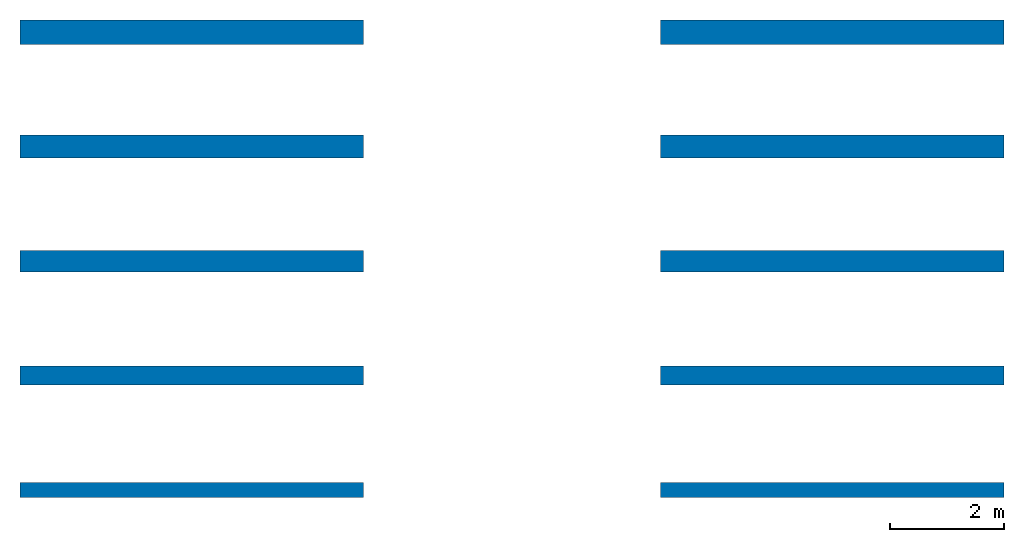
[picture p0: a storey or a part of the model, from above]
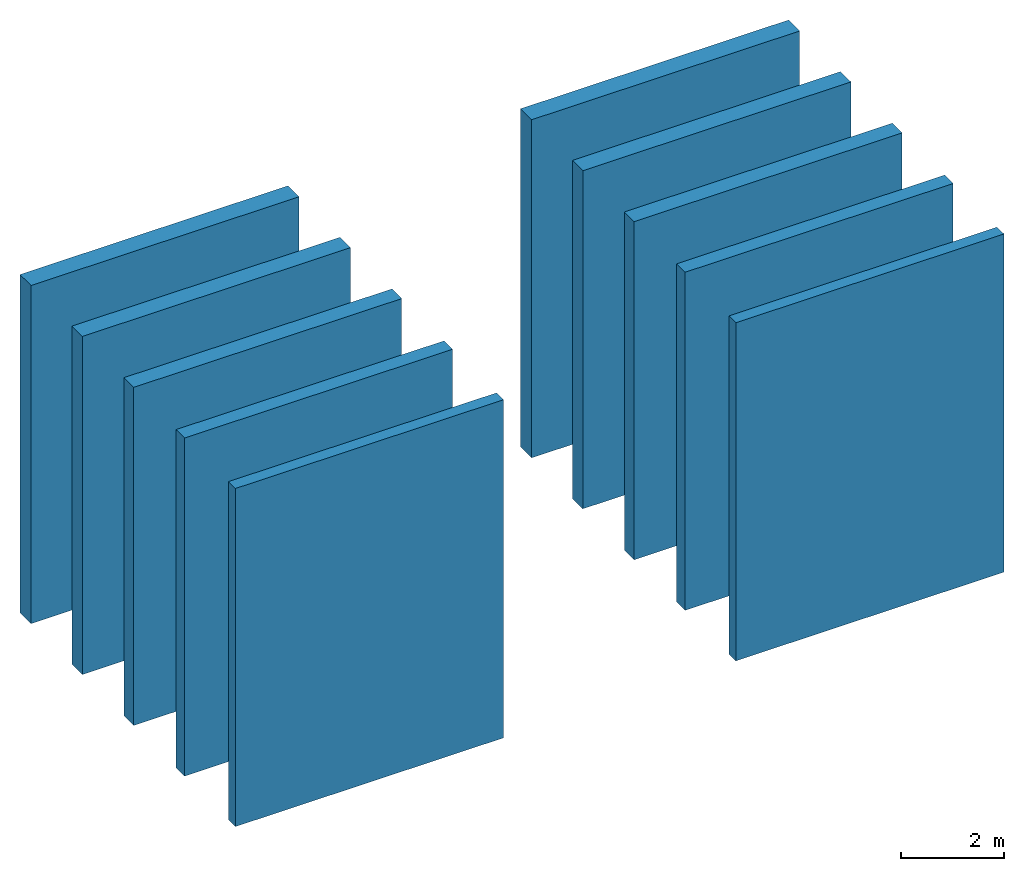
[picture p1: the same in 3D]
Properties of the parts of a building model (IFC2X3)

# File
Description: ViewDefinition [CoordinationView]
File name: Numero
Time: 2019-05-03T09:56:53
Written by: The EXPRESS Data Manager Version 5.02.0100.07 : 28 Aug 2013
Made in: 20150220_1215(x64) - Exporter 16.0.428.0 - Default UI
Comment: STEP Physical File produced by: The EXPRESS Data Manager Version 5.02.0100.07 : 28 Aug 2013 * Module: EDMstepFileFactory/EDMstandAlone * Creation date: Fri May 03 09:56:53 2019 * Host: HP-RS * Database: C:\Users\EKORU_~1\AppData\Local\Temp\{95BD32D2-B268-45CA-9EE8-7F0DB97342BE}\ifc * Database version: 5507 * Database creation date: Fri May 03 09:56:53 2019 * Schema: IFC2X3 * Model: DataRepository.ifc * Model creation date: Fri May 03 09:56:53 2019 * Header model: DataRepository.ifc_HeaderModel * Header model creation date: Fri May 03 09:56:53 2019 * EDMuser: sdai-user * EDMgroup: sdai-group * License ID and type: 5605 : Permanent license. Expiry date: * EDMstepFileFactory options: 020000

# IfcProject, Numero
LongName: Nome; Phase: Stato

# IfcSite, Default
RefLatitude: 41, 47, 59, 999999; RefLongitude: 12, 35, 59, 999999; RefElevation: 0 mm
Altro - Categoria: Informazioni sul progetto; Data di consegna del progetto: Data; Indirizzo del progetto: Immettere l'indirizzo; Nome del cliente: Proprietario; Nome del progetto: Nome; Numero del progetto: Numero; Stato del progetto: Stato

# IfcBuilding
Pset_BuildingCommon - NumberOfStoreys: 1
Altro - Categoria: Informazioni sul progetto; Data di consegna del progetto: Data; Indirizzo del progetto: Immettere l'indirizzo; Nome del cliente: Proprietario; Nome del progetto: Nome; Numero del progetto: Numero; Stato del progetto: Stato

# IfcBuildingStorey, Livello 1
LongName: Livello 1; Elevation: 0 mm
Vincoli - Base quota altimetrica: Punto base progetto; Quota altimetrica: 0 mm
Altro - Categoria: Livelli; Famiglia: Livello: Estremità 8 mm; Famiglia e tipo: Livello: Estremità 8 mm; ID tipo: Livello: Estremità 8 mm; Tipo: Livello: Estremità 8 mm; Nome famiglia: Livello
Dati identità - Strutturale: no; Nome: Livello 1; Piano edificio: yes; Nome del tipo: Estremità 8 mm
Dimensioni - Altezza di calcolo: 0 mm
Grafica - Colore: 0; Modello di linea: Centro; Simbolo: Estremità del livello - Cerchio: Estremità del livello - Cerchio; Simbolo a estremità 1 per default: no; Simbolo a estremità 2 per default: yes; Spessore di linea: 1

# IfcWallStandardCase: Muro di base:Sistema GASBETON Sysmic sp. 269 mm muratura portante, Muro di base:Sistema GASBETON Sysmic sp. 269 mm muratura portante:139188
In: Livello 1
Type - PredefinedType: STANDARD; Material: tonachino colorato ai silicati/silossani di finitura 2 mm, GASBETON Multiraso esterni 5 mm, GASBETON Multicem 15 mm, GASBETON Sysmic 240 mm, GASBETON Incollarasa 5 mm, GASBETON Multiraso interni 2 mm
Type - Altro - Categoria: Muri; Nome famiglia: Muro di base
Type - Costruzione - Funzione: Esterno; Ripiegatura agli inserti: Non ripiegare; Ripiegatura alle estremità: Nessuno; Larghezza: 269 mm
Type - Dati identità - Descrizione: Parete rifinita formata dalla seguente stratigrafia (dall'esterno verso l'interno): tonachino colorato ai silicati/silossani, Multiraso esterni, rete da intonaco GASBETON, Multicem, blocchi GASBETON Sysmic, Incollarasa, rete da intonaco GASBETON, Multira; Installation Guide: http://www.gasbeton.it/wp-content/uploads/2017/11/GASBETON-Guida-alla-progettazione.pdf; Modello: Soluzione muratura esterna portante Gasbeton Sysmic; Nome del tipo: Sistema GASBETON Sysmic sp. 269 mm muratura portante; Product data url: www.gasbeton.it; Produttore: EKORU s.r.l.; Resistenza al fuoco: REI 180; EI 240; Euroclasse A1; Techinical data sheet: http://www.gasbeton.it/download/; URL: http://www.ekoru.it/; Youtube channel: https://www.youtube.com/user/bacchispa
Type - Generale - Edition number: 1; Manufacturer country: Italy; Manufacturer name: EKORU s.r.l.; Product family: walls
Type - Grafica - Colore del retino a dettaglio basso: 0
Type - Materiali e finiture - Materiale strutturale: GASBETON Sysmic; Material main: Autoclaved Aerated Concrete (AAC)
Type - Proprietà analitiche - Ruvidità: 2; Assorbimento: 0.7; Coefficiente di scambio termico (U): 0.409046; Massa termica: 512544; Resistenza termica (R): 2.44471
Altro - Famiglia: Muro di base: Sistema GASBETON Sysmic sp. 269 mm muratura portante; Famiglia e tipo: Muro di base: Sistema GASBETON Sysmic sp. 269 mm muratura portante; ID tipo: Muro di base: Sistema GASBETON Sysmic sp. 269 mm muratura portante; Tipo: Muro di base: Sistema GASBETON Sysmic sp. 269 mm muratura portante
Dimensioni - Area: 48 m2; Lunghezza: 6000 mm; Volume: 12.912 m3
Fasi - Fase di creazione: Fase 1
Strutturale - Attiva modello analitico: no; Strutturale: no; Utilizzo strutturale: Non portante
Vincoli - Delimita il locale: yes; Distanza estensione base: 0 mm; Distanza estensione superiore: 0 mm; La base è associata: no; La parte superiore è associata: no; Linea di ubicazione: Linea d'asse del muro; Offset base: 0 mm; Offset superiore: 0 mm; Relativo a massa: no; Vincolo di base: Livello: Livello 1; Altezza non collegata: 8000 mm
Pset_WallCommon - LoadBearing: no; ExtendToStructure: no; IsExternal: yes; Reference: Sistema GASBETON Sysmic sp. 269 mm muratura portante; FireRating: REI 180; EI 240; Euroclasse A1; ThermalTransmittance: 0.409046 kg/K/s3
Pset_ManufacturerTypeInformation - Manufacturer: EKORU s.r.l.

# IfcWallStandardCase: Muro di base:Sistema GASBETON Sysmic sp. 329 mm muratura portante, Muro di base:Sistema GASBETON Sysmic sp. 329 mm muratura portante:139180
In: Livello 1
Type - PredefinedType: STANDARD; Material: tonachino colorato ai silicati/silossani di finitura 2 mm, GASBETON Multiraso esterni 5 mm, GASBETON Multicem 15 mm, GASBETON Sysmic 300 mm, GASBETON Incollarasa 5 mm, GASBETON Multiraso interni 2 mm
Type - Altro - Categoria: Muri; Nome famiglia: Muro di base
Type - Costruzione - Funzione: Esterno; Ripiegatura agli inserti: Non ripiegare; Ripiegatura alle estremità: Nessuno; Larghezza: 329 mm
Type - Dati identità - Descrizione: Parete rifinita formata dalla seguente stratigrafia (dall'esterno verso l'interno): tonachino colorato ai silicati/silossani, Multiraso esterni, rete da intonaco GASBETON, Multicem, blocchi GASBETON Sysmic, Incollarasa, rete da intonaco GASBETON, Multira; Installation Guide: http://www.gasbeton.it/wp-content/uploads/2017/11/GASBETON-Guida-alla-progettazione.pdf; Modello: Soluzione muratura esterna portante Gasbeton Sysmic; Nome del tipo: Sistema GASBETON Sysmic sp. 329 mm muratura portante; Product data url: www.gasbeton.it; Produttore: EKORU s.r.l.; Resistenza al fuoco: REI 240; Euroclasse A1; Techinical data sheet: http://www.gasbeton.it/download/; URL: http://www.ekoru.it/; Youtube channel: https://www.youtube.com/user/bacchispa
Type - Generale - Edition number: 1; Manufacturer country: Italy; Manufacturer name: EKORU s.r.l.; Product family: walls
Type - Grafica - Colore del retino a dettaglio basso: 0
Type - Materiali e finiture - Materiale strutturale: GASBETON Sysmic; Material main: Autoclaved Aerated Concrete (AAC)
Type - Proprietà analitiche - Ruvidità: 2; Assorbimento: 0.7; Coefficiente di scambio termico (U): 0.329608; Massa termica: 633744; Resistenza termica (R): 3.03391
Altro - Famiglia: Muro di base: Sistema GASBETON Sysmic sp. 329 mm muratura portante; Famiglia e tipo: Muro di base: Sistema GASBETON Sysmic sp. 329 mm muratura portante; ID tipo: Muro di base: Sistema GASBETON Sysmic sp. 329 mm muratura portante; Tipo: Muro di base: Sistema GASBETON Sysmic sp. 329 mm muratura portante
Dimensioni - Area: 48 m2; Lunghezza: 6000 mm; Volume: 15.792 m3
Fasi - Fase di creazione: Fase 1
Strutturale - Attiva modello analitico: no; Strutturale: no; Utilizzo strutturale: Non portante
Vincoli - Delimita il locale: yes; Distanza estensione base: 0 mm; Distanza estensione superiore: 0 mm; La base è associata: no; La parte superiore è associata: no; Linea di ubicazione: Linea d'asse del muro; Offset base: 0 mm; Offset superiore: 0 mm; Relativo a massa: no; Vincolo di base: Livello: Livello 1; Altezza non collegata: 8000 mm
Pset_WallCommon - LoadBearing: no; ExtendToStructure: no; IsExternal: yes; Reference: Sistema GASBETON Sysmic sp. 329 mm muratura portante; FireRating: REI 240; Euroclasse A1; ThermalTransmittance: 0.329608 kg/K/s3
Pset_ManufacturerTypeInformation - Manufacturer: EKORU s.r.l.

# IfcWallStandardCase: Muro di base:Sistema GASBETON Sysmic sp. 379 mm muratura portante, Muro di base:Sistema GASBETON Sysmic sp. 379 mm muratura portante:139172
In: Livello 1
Type - PredefinedType: STANDARD; Material: tonachino colorato ai silicati/silossani di finitura 2 mm, GASBETON Multiraso esterni 5 mm, GASBETON Multicem 15 mm, GASBETON Sysmic 350 mm, GASBETON Incollarasa 5 mm, GASBETON Multiraso interni 2 mm
Type - Altro - Categoria: Muri; Nome famiglia: Muro di base
Type - Costruzione - Funzione: Esterno; Ripiegatura agli inserti: Non ripiegare; Ripiegatura alle estremità: Nessuno; Larghezza: 379 mm
Type - Dati identità - Descrizione: Parete rifinita formata dalla seguente stratigrafia (dall'esterno verso l'interno): tonachino colorato ai silicati/silossani, Multiraso esterni, rete da intonaco GASBETON, Multicem, blocchi GASBETON Sysmic, Incollarasa, rete da intonaco GASBETON, Multira; Installation Guide: http://www.gasbeton.it/wp-content/uploads/2017/11/GASBETON-Guida-alla-progettazione.pdf; Modello: Soluzione muratura esterna portante Gasbeton Sysmic; Nome del tipo: Sistema GASBETON Sysmic sp. 379 mm muratura portante; Product data url: www.gasbeton.it; Produttore: EKORU s.r.l.; Resistenza al fuoco: REI 240; Euroclasse A1; Techinical data sheet: http://www.gasbeton.it/download/; URL: http://www.ekoru.it/; Youtube channel: https://www.youtube.com/user/bacchispa
Type - Generale - Edition number: 1; Manufacturer country: Italy; Manufacturer name: EKORU s.r.l.; Product family: walls
Type - Grafica - Colore del retino a dettaglio basso: 0
Type - Materiali e finiture - Materiale strutturale: GASBETON Sysmic; Material main: Autoclaved Aerated Concrete (AAC)
Type - Proprietà analitiche - Ruvidità: 2; Assorbimento: 0.7; Coefficiente di scambio termico (U): 0.283695; Massa termica: 734744; Resistenza termica (R): 3.52491
Altro - Famiglia: Muro di base: Sistema GASBETON Sysmic sp. 379 mm muratura portante; Famiglia e tipo: Muro di base: Sistema GASBETON Sysmic sp. 379 mm muratura portante; ID tipo: Muro di base: Sistema GASBETON Sysmic sp. 379 mm muratura portante; Tipo: Muro di base: Sistema GASBETON Sysmic sp. 379 mm muratura portante
Dimensioni - Area: 48 m2; Lunghezza: 6000 mm; Volume: 18.192 m3
Fasi - Fase di creazione: Fase 1
Strutturale - Attiva modello analitico: no; Strutturale: no; Utilizzo strutturale: Non portante
Vincoli - Delimita il locale: yes; Distanza estensione base: 0 mm; Distanza estensione superiore: 0 mm; La base è associata: no; La parte superiore è associata: no; Linea di ubicazione: Linea d'asse del muro; Offset base: 0 mm; Offset superiore: 0 mm; Relativo a massa: no; Vincolo di base: Livello: Livello 1; Altezza non collegata: 8000 mm
Pset_WallCommon - LoadBearing: no; ExtendToStructure: no; IsExternal: yes; Reference: Sistema GASBETON Sysmic sp. 379 mm muratura portante; FireRating: REI 240; Euroclasse A1; ThermalTransmittance: 0.283695 kg/K/s3
Pset_ManufacturerTypeInformation - Manufacturer: EKORU s.r.l.

# IfcWallStandardCase: Muro di base:Sistema GASBETON Sysmic sp. 404 mm muratura portante, Muro di base:Sistema GASBETON Sysmic sp. 404 mm muratura portante:139164
In: Livello 1
Type - PredefinedType: STANDARD; Material: tonachino colorato ai silicati/silossani di finitura 2 mm, GASBETON Multiraso esterni 5 mm, GASBETON Multicem 15 mm, GASBETON Sysmic 375 mm, GASBETON Incollarasa 5 mm, GASBETON Multiraso interni 2 mm
Type - Altro - Categoria: Muri; Nome famiglia: Muro di base
Type - Costruzione - Funzione: Esterno; Ripiegatura agli inserti: Non ripiegare; Ripiegatura alle estremità: Nessuno; Larghezza: 404 mm
Type - Dati identità - Descrizione: Parete rifinita formata dalla seguente stratigrafia (dall'esterno verso l'interno): tonachino colorato ai silicati/silossani, Multiraso esterni, rete da intonaco GASBETON, Multicem, blocchi GASBETON Sysmic, Incollarasa, rete da intonaco GASBETON, Multira; Installation Guide: http://www.gasbeton.it/wp-content/uploads/2017/11/GASBETON-Guida-alla-progettazione.pdf; Modello: Soluzione muratura esterna portante Gasbeton Sysmic; Nome del tipo: Sistema GASBETON Sysmic sp. 404 mm muratura portante; Product data url: www.gasbeton.it; Produttore: EKORU s.r.l.; Resistenza al fuoco: REI 240; Euroclasse A1; Techinical data sheet: http://www.gasbeton.it/download/; URL: http://www.ekoru.it/; Youtube channel: https://www.youtube.com/user/bacchispa
Type - Generale - Edition number: 1; Manufacturer country: Italy; Manufacturer name: EKORU s.r.l.; Product family: walls
Type - Grafica - Colore del retino a dettaglio basso: 0
Type - Materiali e finiture - Materiale strutturale: GASBETON Sysmic; Material main: Autoclaved Aerated Concrete (AAC)
Type - Proprietà analitiche - Ruvidità: 2; Assorbimento: 0.7; Coefficiente di scambio termico (U): 0.265223; Massa termica: 785244; Resistenza termica (R): 3.77041
Altro - Famiglia: Muro di base: Sistema GASBETON Sysmic sp. 404 mm muratura portante; Famiglia e tipo: Muro di base: Sistema GASBETON Sysmic sp. 404 mm muratura portante; ID tipo: Muro di base: Sistema GASBETON Sysmic sp. 404 mm muratura portante; Tipo: Muro di base: Sistema GASBETON Sysmic sp. 404 mm muratura portante
Dimensioni - Area: 48 m2; Lunghezza: 6000 mm; Volume: 19.392 m3
Fasi - Fase di creazione: Fase 1
Strutturale - Attiva modello analitico: no; Strutturale: no; Utilizzo strutturale: Non portante
Vincoli - Delimita il locale: yes; Distanza estensione base: 0 mm; Distanza estensione superiore: 0 mm; La base è associata: no; La parte superiore è associata: no; Linea di ubicazione: Linea d'asse del muro; Offset base: 0 mm; Offset superiore: 0 mm; Relativo a massa: no; Vincolo di base: Livello: Livello 1; Altezza non collegata: 8000 mm
Pset_WallCommon - LoadBearing: no; ExtendToStructure: no; IsExternal: yes; Reference: Sistema GASBETON Sysmic sp. 404 mm muratura portante; FireRating: REI 240; Euroclasse A1; ThermalTransmittance: 0.265223 kg/K/s3
Pset_ManufacturerTypeInformation - Manufacturer: EKORU s.r.l.

# IfcWallStandardCase: Muro di base:Sistema GASBETON Sysmic sp. 429 mm muratura portante, Muro di base:Sistema GASBETON Sysmic sp. 429 mm muratura portante:139156
In: Livello 1
Type - PredefinedType: STANDARD; Material: tonachino colorato ai silicati/silossani di finitura 2 mm, GASBETON Multiraso esterni 5 mm, GASBETON Multicem 15 mm, GASBETON Sysmic 400 mm, GASBETON Incollarasa 5 mm, GASBETON Multiraso interni 2 mm
Type - Altro - Categoria: Muri; Nome famiglia: Muro di base
Type - Costruzione - Funzione: Esterno; Larghezza: 429 mm; Ripiegatura agli inserti: Non ripiegare; Ripiegatura alle estremità: Nessuno
Type - Dati identità - Descrizione: Parete rifinita formata dalla seguente stratigrafia (dall'esterno verso l'interno): tonachino colorato ai silicati/silossani, Multiraso esterni, rete da intonaco GASBETON, Multicem, blocchi GASBETON Sysmic, Incollarasa, rete da intonaco GASBETON, Multira; Installation Guide: http://www.gasbeton.it/wp-content/uploads/2017/11/GASBETON-Guida-alla-progettazione.pdf; Modello: Soluzione muratura esterna portante Gasbeton Sysmic; Nome del tipo: Sistema GASBETON Sysmic sp. 429 mm muratura portante; Product data url: www.gasbeton.it; Produttore: EKORU s.r.l.; Resistenza al fuoco: REI 240; Euroclasse A1; Techinical data sheet: http://www.gasbeton.it/download/; URL: http://www.ekoru.it/; Youtube channel: https://www.youtube.com/user/bacchispa
Type - Generale - Edition number: 1; Manufacturer country: Italy; Manufacturer name: EKORU s.r.l.; Product family: walls
Type - Grafica - Colore del retino a dettaglio basso: 0
Type - Materiali e finiture - Materiale strutturale: GASBETON Sysmic; Material main: Autoclaved Aerated Concrete (AAC)
Type - Proprietà analitiche - Assorbimento: 0.7; Coefficiente di scambio termico (U): 0.24901; Massa termica: 835744; Resistenza termica (R): 4.01591; Ruvidità: 2
Altro - Famiglia: Muro di base: Sistema GASBETON Sysmic sp. 429 mm muratura portante; Famiglia e tipo: Muro di base: Sistema GASBETON Sysmic sp. 429 mm muratura portante; ID tipo: Muro di base: Sistema GASBETON Sysmic sp. 429 mm muratura portante; Tipo: Muro di base: Sistema GASBETON Sysmic sp. 429 mm muratura portante
Dimensioni - Area: 48 m2; Lunghezza: 6000 mm; Volume: 20.592 m3
Fasi - Fase di creazione: Fase 1
Strutturale - Attiva modello analitico: no; Strutturale: no; Utilizzo strutturale: Non portante
Vincoli - Altezza non collegata: 8000 mm; Delimita il locale: yes; Distanza estensione base: 0 mm; Distanza estensione superiore: 0 mm; La base è associata: no; La parte superiore è associata: no; Linea di ubicazione: Linea d'asse del muro; Offset base: 0 mm; Offset superiore: 0 mm; Relativo a massa: no; Vincolo di base: Livello: Livello 1
Pset_WallCommon - Reference: Sistema GASBETON Sysmic sp. 429 mm muratura portante; LoadBearing: no; ExtendToStructure: no; IsExternal: yes; FireRating: REI 240; Euroclasse A1; ThermalTransmittance: 0.24901 kg/K/s3
Pset_ManufacturerTypeInformation - Manufacturer: EKORU s.r.l.

# IfcWallStandardCase: Muro di base:Sistema GASBETON Sysmic+ IDRO sp. 269 mm muratura portante, Muro di base:Sistema GASBETON Sysmic+ IDRO sp. 269 mm muratura portante:139192
In: Livello 1
Type - PredefinedType: STANDARD; Material: tonachino colorato ai silicati/silossani di finitura 2 mm, GASBETON Multiraso esterni 5 mm, GASBETON Multicem 15 mm, GASBETON Sysmic 240 mm, GASBETON Incollarasa 5 mm, GASBETON Multiraso interni 2 mm
Type - Altro - Categoria: Muri; Nome famiglia: Muro di base
Type - Costruzione - Funzione: Esterno; Ripiegatura agli inserti: Non ripiegare; Ripiegatura alle estremità: Nessuno; Larghezza: 269 mm
Type - Dati identità - Descrizione: Parete rifinita formata dalla seguente stratigrafia (dall'esterno verso l'interno): tonachino colorato ai silicati/silossani, Multiraso esterni, rete da intonaco GASBETON, Multicem, blocchi GASBETON Sysmic, Incollarasa, rete da intonaco GASBETON, Multira; Installation Guide: http://www.gasbeton.it/wp-content/uploads/2017/11/GASBETON-Guida-alla-progettazione.pdf; Modello: Soluzione muratura esterna portante Gasbeton Sysmic con primo corso idrofobizzato; Nome del tipo: Sistema GASBETON Sysmic+ IDRO sp. 269 mm muratura portante; Product data url: www.gasbeton.it; Produttore: EKORU s.r.l.; Resistenza al fuoco: REI 180; EI 240; Euroclasse A1; Techinical data sheet: http://www.gasbeton.it/download/; URL: http://www.ekoru.it/; Youtube channel: https://www.youtube.com/user/bacchispa
Type - Generale - Edition number: 1; Manufacturer country: Italy; Manufacturer name: EKORU s.r.l.; Product family: walls
Type - Grafica - Colore del retino a dettaglio basso: 0
Type - Materiali e finiture - Materiale strutturale: GASBETON Sysmic; Material main: Autoclaved Aerated Concrete (AAC)
Type - Proprietà analitiche - Ruvidità: 2; Assorbimento: 0.7; Coefficiente di scambio termico (U): 0.245737; Massa termica: 732384; Resistenza termica (R): 4.06939
Altro - Famiglia: Muro di base: Sistema GASBETON Sysmic+ IDRO sp. 269 mm muratura portante; Famiglia e tipo: Muro di base: Sistema GASBETON Sysmic+ IDRO sp. 269 mm muratura portante; ID tipo: Muro di base: Sistema GASBETON Sysmic+ IDRO sp. 269 mm muratura portante; Tipo: Muro di base: Sistema GASBETON Sysmic+ IDRO sp. 269 mm muratura portante
Dimensioni - Area: 48 m2; Lunghezza: 6000 mm; Volume: 12.912 m3
Fasi - Fase di creazione: Fase 1
Strutturale - Attiva modello analitico: no; Strutturale: no; Utilizzo strutturale: Non portante
Vincoli - Delimita il locale: yes; Distanza estensione base: 0 mm; Distanza estensione superiore: 0 mm; La base è associata: no; La parte superiore è associata: no; Linea di ubicazione: Linea d'asse del muro; Offset base: 0 mm; Offset superiore: 0 mm; Relativo a massa: no; Vincolo di base: Livello: Livello 1; Altezza non collegata: 8000 mm
Pset_WallCommon - LoadBearing: no; ExtendToStructure: no; IsExternal: yes; Reference: Sistema GASBETON Sysmic+ IDRO sp. 269 mm muratura portante; FireRating: REI 180; EI 240; Euroclasse A1; ThermalTransmittance: 0.245737 kg/K/s3
Pset_ManufacturerTypeInformation - Manufacturer: EKORU s.r.l.

# IfcWallStandardCase: Muro di base:Sistema GASBETON Sysmic+ IDRO sp. 329 mm muratura portante, Muro di base:Sistema GASBETON Sysmic+ IDRO sp. 329 mm muratura portante:153701
In: Livello 1
Type - PredefinedType: STANDARD; Material: tonachino colorato ai silicati/silossani di finitura 2 mm, GASBETON Multiraso esterni 5 mm, GASBETON Multicem 15 mm, GASBETON Sysmic 300 mm, GASBETON Incollarasa 5 mm, GASBETON Multiraso interni 2 mm
Type - Altro - Categoria: Muri; Nome famiglia: Muro di base
Type - Costruzione - Funzione: Esterno; Ripiegatura agli inserti: Non ripiegare; Ripiegatura alle estremità: Nessuno; Larghezza: 329 mm
Type - Dati identità - Descrizione: Parete rifinita formata dalla seguente stratigrafia (dall'esterno verso l'interno): tonachino colorato ai silicati/silossani, Multiraso esterni, rete da intonaco GASBETON, Multicem, blocchi GASBETON Sysmic, Incollarasa, rete da intonaco GASBETON, Multira; Installation Guide: http://www.gasbeton.it/wp-content/uploads/2017/11/GASBETON-Guida-alla-progettazione.pdf; Modello: Soluzione muratura esterna portante Gasbeton Sysmic con primo corso idrofobizzato; Nome del tipo: Sistema GASBETON Sysmic+ IDRO sp. 329 mm muratura portante; Product data url: www.gasbeton.it; Produttore: EKORU s.r.l.; Resistenza al fuoco: REI 240; Euroclasse A1; Techinical data sheet: http://www.gasbeton.it/download/; URL: http://www.ekoru.it/; Youtube channel: https://www.youtube.com/user/bacchispa
Type - Generale - Edition number: 1; Manufacturer country: Italy; Manufacturer name: EKORU s.r.l.; Product family: walls
Type - Grafica - Colore del retino a dettaglio basso: 0
Type - Materiali e finiture - Materiale strutturale: GASBETON Sysmic; Material main: Autoclaved Aerated Concrete (AAC)
Type - Proprietà analitiche - Ruvidità: 2; Assorbimento: 0.7; Coefficiente di scambio termico (U): 0.197443; Massa termica: 908544; Resistenza termica (R): 5.06475
Altro - Famiglia: Muro di base: Sistema GASBETON Sysmic+ IDRO sp. 329 mm muratura portante; Famiglia e tipo: Muro di base: Sistema GASBETON Sysmic+ IDRO sp. 329 mm muratura portante; ID tipo: Muro di base: Sistema GASBETON Sysmic+ IDRO sp. 329 mm muratura portante; Tipo: Muro di base: Sistema GASBETON Sysmic+ IDRO sp. 329 mm muratura portante
Dimensioni - Area: 48 m2; Lunghezza: 6000 mm; Volume: 15.792 m3
Fasi - Fase di creazione: Fase 1
Strutturale - Attiva modello analitico: no; Strutturale: no; Utilizzo strutturale: Non portante
Vincoli - Delimita il locale: yes; Distanza estensione base: 0 mm; Distanza estensione superiore: 0 mm; La base è associata: no; La parte superiore è associata: no; Linea di ubicazione: Linea d'asse del muro; Offset base: 0 mm; Offset superiore: 0 mm; Relativo a massa: no; Vincolo di base: Livello: Livello 1; Altezza non collegata: 8000 mm
Pset_WallCommon - LoadBearing: no; ExtendToStructure: no; IsExternal: yes; Reference: Sistema GASBETON Sysmic+ IDRO sp. 329 mm muratura portante; FireRating: REI 240; Euroclasse A1; ThermalTransmittance: 0.197443 kg/K/s3
Pset_ManufacturerTypeInformation - Manufacturer: EKORU s.r.l.

# IfcWallStandardCase: Muro di base:Sistema GASBETON Sysmic+ IDRO sp. 379 mm muratura portante, Muro di base:Sistema GASBETON Sysmic+ IDRO sp. 379 mm muratura portante:153700
In: Livello 1
Type - PredefinedType: STANDARD; Material: tonachino colorato ai silicati/silossani di finitura 2 mm, GASBETON Multiraso esterni 5 mm, GASBETON Multicem 15 mm, GASBETON Sysmic 350 mm, GASBETON Incollarasa 5 mm, GASBETON Multiraso interni 2 mm
Type - Altro - Categoria: Muri; Nome famiglia: Muro di base
Type - Costruzione - Funzione: Esterno; Ripiegatura agli inserti: Non ripiegare; Ripiegatura alle estremità: Nessuno; Larghezza: 379 mm
Type - Dati identità - Descrizione: Parete rifinita formata dalla seguente stratigrafia (dall'esterno verso l'interno): tonachino colorato ai silicati/silossani, Multiraso esterni, rete da intonaco GASBETON, Multicem, blocchi GASBETON Sysmic, Incollarasa, rete da intonaco GASBETON, Multira; Installation Guide: http://www.gasbeton.it/wp-content/uploads/2017/11/GASBETON-Guida-alla-progettazione.pdf; Modello: Soluzione muratura esterna portante Gasbeton Sysmic con primo corso idrofobizzato; Nome del tipo: Sistema GASBETON Sysmic+ IDRO sp. 379 mm muratura portante; Product data url: www.gasbeton.it; Produttore: EKORU s.r.l.; Resistenza al fuoco: REI 240; Euroclasse A1; Techinical data sheet: http://www.gasbeton.it/download/; URL: http://www.ekoru.it/; Youtube channel: https://www.youtube.com/user/bacchispa
Type - Generale - Edition number: 1; Manufacturer country: Italy; Manufacturer name: EKORU s.r.l.; Product family: walls
Type - Grafica - Colore del retino a dettaglio basso: 0
Type - Materiali e finiture - Materiale strutturale: GASBETON Sysmic; Material main: Autoclaved Aerated Concrete (AAC)
Type - Proprietà analitiche - Ruvidità: 2; Assorbimento: 0.7; Coefficiente di scambio termico (U): 0.169658; Massa termica: 1055344; Resistenza termica (R): 5.89422
Altro - Famiglia: Muro di base: Sistema GASBETON Sysmic+ IDRO sp. 379 mm muratura portante; Famiglia e tipo: Muro di base: Sistema GASBETON Sysmic+ IDRO sp. 379 mm muratura portante; ID tipo: Muro di base: Sistema GASBETON Sysmic+ IDRO sp. 379 mm muratura portante; Tipo: Muro di base: Sistema GASBETON Sysmic+ IDRO sp. 379 mm muratura portante
Dimensioni - Area: 48 m2; Lunghezza: 6000 mm; Volume: 18.192 m3
Fasi - Fase di creazione: Fase 1
Strutturale - Attiva modello analitico: no; Strutturale: no; Utilizzo strutturale: Non portante
Vincoli - Delimita il locale: yes; Distanza estensione base: 0 mm; Distanza estensione superiore: 0 mm; La base è associata: no; La parte superiore è associata: no; Linea di ubicazione: Linea d'asse del muro; Offset base: 0 mm; Offset superiore: 0 mm; Relativo a massa: no; Vincolo di base: Livello: Livello 1; Altezza non collegata: 8000 mm
Pset_WallCommon - LoadBearing: no; ExtendToStructure: no; IsExternal: yes; Reference: Sistema GASBETON Sysmic+ IDRO sp. 379 mm muratura portante; FireRating: REI 240; Euroclasse A1; ThermalTransmittance: 0.169658 kg/K/s3
Pset_ManufacturerTypeInformation - Manufacturer: EKORU s.r.l.

# IfcWallStandardCase: Muro di base:Sistema GASBETON Sysmic+ IDRO sp. 404 mm muratura portante, Muro di base:Sistema GASBETON Sysmic+ IDRO sp. 404 mm muratura portante:153699
In: Livello 1
Type - PredefinedType: STANDARD; Material: tonachino colorato ai silicati/silossani di finitura 2 mm, GASBETON Multiraso esterni 5 mm, GASBETON Multicem 15 mm, GASBETON Sysmic 375 mm, GASBETON Incollarasa 5 mm, GASBETON Multiraso interni 2 mm
Type - Altro - Categoria: Muri; Nome famiglia: Muro di base
Type - Costruzione - Funzione: Esterno; Ripiegatura agli inserti: Non ripiegare; Ripiegatura alle estremità: Nessuno; Larghezza: 404 mm
Type - Dati identità - Descrizione: Parete rifinita formata dalla seguente stratigrafia (dall'esterno verso l'interno): tonachino colorato ai silicati/silossani, Multiraso esterni, rete da intonaco GASBETON, Multicem, blocchi GASBETON Sysmic, Incollarasa, rete da intonaco GASBETON, Multira; Installation Guide: http://www.gasbeton.it/wp-content/uploads/2017/11/GASBETON-Guida-alla-progettazione.pdf; Modello: Soluzione muratura esterna portante Gasbeton Sysmic con primo corso idrofobizzato; Nome del tipo: Sistema GASBETON Sysmic+ IDRO sp. 404 mm muratura portante; Product data url: www.gasbeton.it; Produttore: EKORU s.r.l.; Resistenza al fuoco: REI 240; Euroclasse A1; Techinical data sheet: http://www.gasbeton.it/download/; URL: http://www.ekoru.it/; Youtube channel: https://www.youtube.com/user/bacchispa
Type - Generale - Edition number: 1; Manufacturer country: Italy; Manufacturer name: EKORU s.r.l.; Product family: walls
Type - Grafica - Colore del retino a dettaglio basso: 0
Type - Materiali e finiture - Materiale strutturale: GASBETON Sysmic; Material main: Autoclaved Aerated Concrete (AAC)
Type - Proprietà analitiche - Ruvidità: 2; Assorbimento: 0.7; Coefficiente di scambio termico (U): 0.158505; Massa termica: 1128744; Resistenza termica (R): 6.30896
Altro - Famiglia: Muro di base: Sistema GASBETON Sysmic+ IDRO sp. 404 mm muratura portante; Famiglia e tipo: Muro di base: Sistema GASBETON Sysmic+ IDRO sp. 404 mm muratura portante; ID tipo: Muro di base: Sistema GASBETON Sysmic+ IDRO sp. 404 mm muratura portante; Tipo: Muro di base: Sistema GASBETON Sysmic+ IDRO sp. 404 mm muratura portante
Dimensioni - Area: 48 m2; Lunghezza: 6000 mm; Volume: 19.392 m3
Fasi - Fase di creazione: Fase 1
Strutturale - Attiva modello analitico: no; Strutturale: no; Utilizzo strutturale: Non portante
Vincoli - Delimita il locale: yes; Distanza estensione base: 0 mm; Distanza estensione superiore: 0 mm; La base è associata: no; La parte superiore è associata: no; Linea di ubicazione: Linea d'asse del muro; Offset base: 0 mm; Offset superiore: 0 mm; Relativo a massa: no; Vincolo di base: Livello: Livello 1; Altezza non collegata: 8000 mm
Pset_WallCommon - LoadBearing: no; ExtendToStructure: no; IsExternal: yes; Reference: Sistema GASBETON Sysmic+ IDRO sp. 404 mm muratura portante; FireRating: REI 240; Euroclasse A1; ThermalTransmittance: 0.158505 kg/K/s3
Pset_ManufacturerTypeInformation - Manufacturer: EKORU s.r.l.

# IfcWallStandardCase: Muro di base:Sistema GASBETON Sysmic+ IDRO sp. 429 mm muratura portante, Muro di base:Sistema GASBETON Sysmic+ IDRO sp. 429 mm muratura portante:153698
In: Livello 1
Type - PredefinedType: STANDARD; Material: tonachino colorato ai silicati/silossani di finitura 2 mm, GASBETON Multiraso esterni 5 mm, GASBETON Multicem 15 mm, GASBETON Sysmic 400 mm, GASBETON Incollarasa 5 mm, GASBETON Multiraso interni 2 mm
Type - Altro - Categoria: Muri; Nome famiglia: Muro di base
Type - Costruzione - Funzione: Esterno; Ripiegatura agli inserti: Non ripiegare; Ripiegatura alle estremità: Nessuno; Larghezza: 429 mm
Type - Dati identità - Descrizione: Parete rifinita formata dalla seguente stratigrafia (dall'esterno verso l'interno): tonachino colorato ai silicati/silossani, Multiraso esterni, rete da intonaco GASBETON, Multicem, blocchi GASBETON Sysmic, Incollarasa, rete da intonaco GASBETON, Multira; Installation Guide: http://www.gasbeton.it/wp-content/uploads/2017/11/GASBETON-Guida-alla-progettazione.pdf; Modello: Soluzione muratura esterna portante Gasbeton Sysmic con primo corso idrofobizzato; Nome del tipo: Sistema GASBETON Sysmic+ IDRO sp. 429 mm muratura portante; Product data url: www.gasbeton.it; Produttore: EKORU s.r.l.; Resistenza al fuoco: REI 240; Euroclasse A1; Techinical data sheet: http://www.gasbeton.it/download/; URL: http://www.ekoru.it/; Youtube channel: https://www.youtube.com/user/bacchispa
Type - Generale - Edition number: 1; Manufacturer country: Italy; Manufacturer name: EKORU s.r.l.; Product family: walls
Type - Grafica - Colore del retino a dettaglio basso: 0
Type - Materiali e finiture - Materiale strutturale: GASBETON Sysmic; Material main: Autoclaved Aerated Concrete (AAC)
Type - Proprietà analitiche - Ruvidità: 2; Assorbimento: 0.7; Coefficiente di scambio termico (U): 0.148728; Massa termica: 1202144; Resistenza termica (R): 6.7237
Altro - Famiglia: Muro di base: Sistema GASBETON Sysmic+ IDRO sp. 429 mm muratura portante; Famiglia e tipo: Muro di base: Sistema GASBETON Sysmic+ IDRO sp. 429 mm muratura portante; ID tipo: Muro di base: Sistema GASBETON Sysmic+ IDRO sp. 429 mm muratura portante; Tipo: Muro di base: Sistema GASBETON Sysmic+ IDRO sp. 429 mm muratura portante
Dimensioni - Area: 48 m2; Lunghezza: 6000 mm; Volume: 20.592 m3
Fasi - Fase di creazione: Fase 1
Strutturale - Attiva modello analitico: no; Strutturale: no; Utilizzo strutturale: Non portante
Vincoli - Delimita il locale: yes; Distanza estensione base: 0 mm; Distanza estensione superiore: 0 mm; La base è associata: no; La parte superiore è associata: no; Linea di ubicazione: Linea d'asse del muro; Offset base: 0 mm; Offset superiore: 0 mm; Relativo a massa: no; Vincolo di base: Livello: Livello 1; Altezza non collegata: 8000 mm
Pset_WallCommon - LoadBearing: no; ExtendToStructure: no; IsExternal: yes; Reference: Sistema GASBETON Sysmic+ IDRO sp. 429 mm muratura portante; FireRating: REI 240; Euroclasse A1; ThermalTransmittance: 0.148728 kg/K/s3
Pset_ManufacturerTypeInformation - Manufacturer: EKORU s.r.l.
